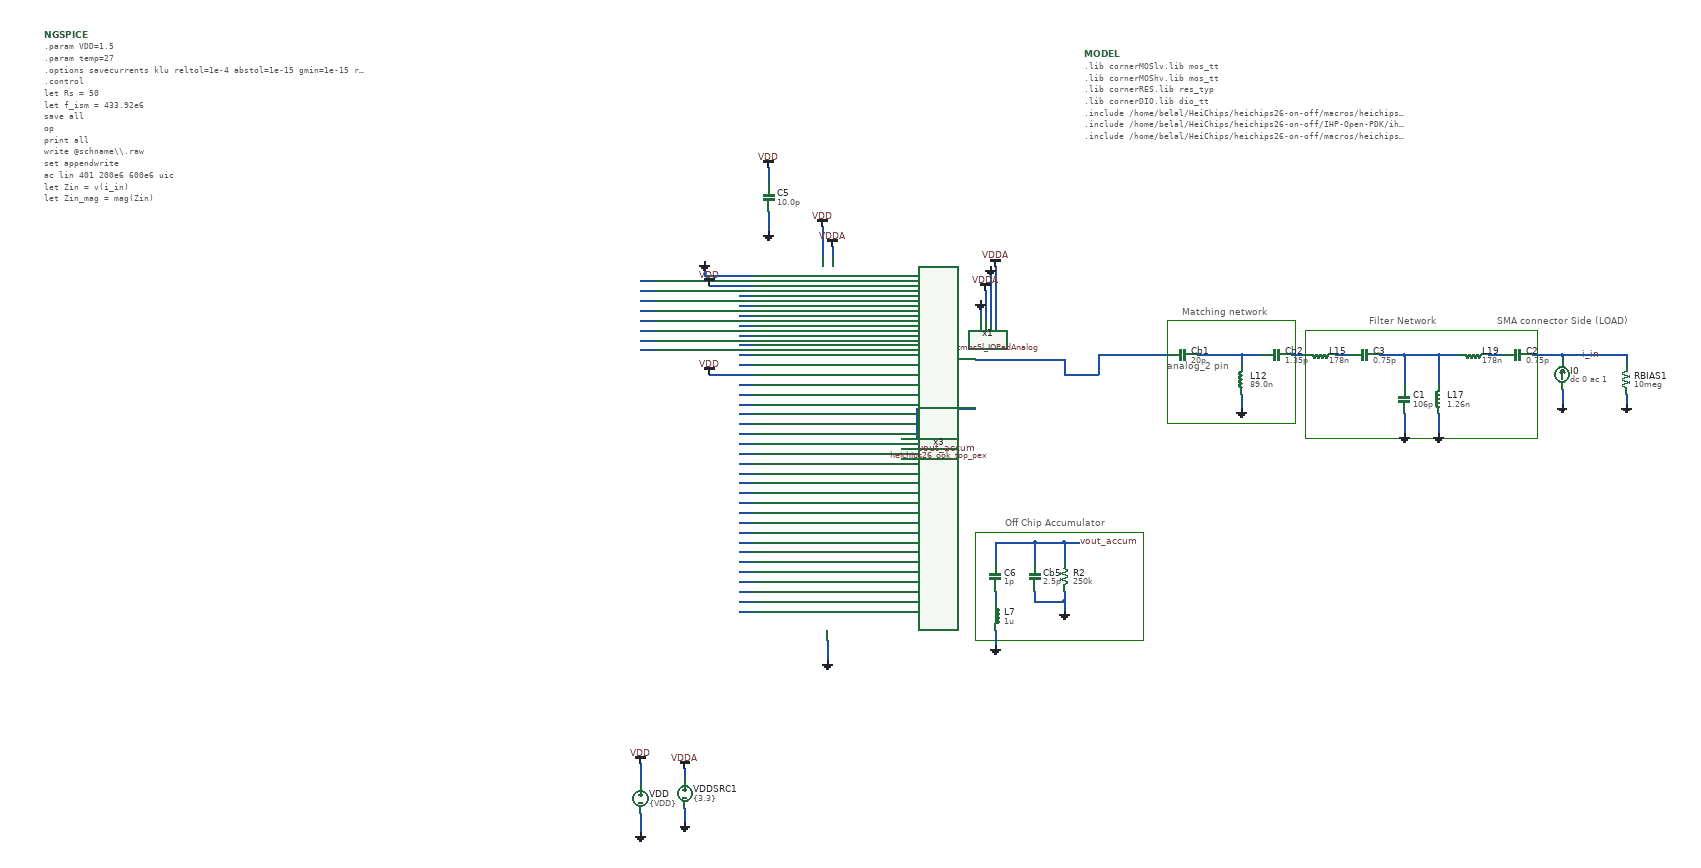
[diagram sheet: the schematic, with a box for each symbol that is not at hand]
v {xschem version=3.4.8RC file_version=1.3}
G {}
K {}
V {}
S {}
F {}
E {}
P 4 6 820 -740 820 -540 1160 -540 1160 -760 820 -760 820 -740 {}
P 4 7 1220 -1190 1470 -1190 1470 -980 1210 -980 1210 -1190 1230 -1190 1220 -1190 {}
P 4 5 1490 -1170 1960 -1170 1960 -950 1490 -950 1490 -1170 {}
T {Off Chip Accumulator} 880 -790 0 0 0.4 0.4 {}
T {Matching network} 1240 -1220 0 0 0.4 0.4 {}
T {Filter Network} 1620 -1200 0 0 0.4 0.4 {}
T {SMA connector Side (LOAD)} 1880 -1200 0 0 0.4 0.4 {}
T {analog_2 pin} 1210 -1110 1 0 0.4 0.4 {}
N 830 -1230 830 -1200 {lab=GND}
N 850 -1300 850 -1180 {lab=GND}
N 860 -1300 860 -1170 {lab=VDDA}
N 840 -1250 840 -1190 {lab=VDDA}
N 820 -1110 1000 -1110 {lab=#net1}
N 1000 -1110 1000 -1080 {lab=#net1}
N 510 -1380 510 -1320 {lab=VDD}
N 530 -1340 530 -1320 {lab=VDDA}
N 280 -1260 370 -1260 {lab=VDD}
N 340 -660 370 -660 {lab=#net2}
N 340 -640 370 -640 {lab=#net3}
N 340 -620 370 -620 {lab=#net4}
N 340 -600 370 -600 {lab=#net5}
N 670 -930 700 -930 {lab=vout_accum}
N 340 -1240 370 -1240 {lab=#net6}
N 340 -1220 370 -1220 {lab=#net7}
N 340 -1200 370 -1200 {lab=#net8}
N 340 -1180 370 -1180 {lab=#net9}
N 340 -1160 370 -1160 {lab=#net10}
N 340 -1140 370 -1140 {lab=#net11}
N 340 -1120 370 -1120 {lab=#net12}
N 340 -1100 370 -1100 {lab=#net13}
N 340 -1060 370 -1060 {lab=#net14}
N 340 -1040 370 -1040 {lab=#net15}
N 340 -1020 370 -1020 {lab=#net16}
N 340 -1000 370 -1000 {lab=#net17}
N 340 -980 370 -980 {lab=#net18}
N 340 -960 370 -960 {lab=#net19}
N 340 -940 370 -940 {lab=#net20}
N 340 -920 370 -920 {lab=#net21}
N 340 -900 370 -900 {lab=#net22}
N 340 -880 370 -880 {lab=#net23}
N 340 -860 370 -860 {lab=#net24}
N 340 -840 370 -840 {lab=#net25}
N 340 -820 370 -820 {lab=#net26}
N 340 -800 370 -800 {lab=#net27}
N 340 -780 370 -780 {lab=#net28}
N 340 -760 370 -760 {lab=#net29}
N 340 -740 370 -740 {lab=#net30}
N 340 -720 370 -720 {lab=#net31}
N 340 -700 370 -700 {lab=#net32}
N 340 -680 370 -680 {lab=#net33}
N 280 -1080 370 -1080 {lab=VDD}
N 140 -1270 170 -1270 {lab=#net34}
N 140 -1250 170 -1250 {lab=#net35}
N 140 -1230 170 -1230 {lab=#net36}
N 140 -1210 170 -1210 {lab=#net37}
N 140 -1190 170 -1190 {lab=#net38}
N 140 -1170 170 -1170 {lab=#net39}
N 140 -1150 170 -1150 {lab=#net40}
N 140 -1130 170 -1130 {lab=#net41}
N 520 -540 520 -500 {lab=GND}
N 270 -1310 270 -1280 {lab=GND}
N 270 -1280 370 -1280 {lab=GND}
N 400 -1500 400 -1470 {lab=VDD}
N 400 -1410 400 -1370 {lab=GND}
N 670 -950 700 -950 {lab=#net42}
N 1000 -740 1000 -700 {lab=vout_accum}
N 940 -740 940 -700 {lab=vout_accum}
N 940 -740 1000 -740 {lab=vout_accum}
N 940 -640 940 -620 {lab=GND}
N 940 -620 1000 -620 {lab=GND}
N 1000 -640 1000 -620 {lab=GND}
N 1000 -620 1000 -600 {lab=GND}
N 860 -560 860 -530 {lab=GND}
N 860 -740 860 -700 {lab=vout_accum}
N 860 -640 860 -620 {lab=#net43}
N 1000 -740 1030 -740 {lab=vout_accum}
N 860 -740 940 -740 {lab=vout_accum}
N 670 -910 700 -910 {lab=#net44}
N 2010 -1050 2010 -1020 {lab=GND}
N 2010 -1120 2010 -1110 {lab=i_in}
N 2140 -1040 2140 -1020 {lab=GND}
N 2140 -1120 2140 -1100 {lab=i_in}
N 700 -1010 820 -1010 {lab=#net42}
N 700 -1010 700 -950 {lab=#net42}
N 140 -290 140 -250 {lab=VDD}
N 140 -190 140 -150 {lab=GND}
N 230 -280 230 -260 {lab=VDDA}
N 230 -200 230 -170 {lab=GND}
N 1360 -1120 1360 -1100 {lab=#net45}
N 1360 -1040 1360 -1010 {lab=GND}
N 1000 -1080 1070 -1080 {lab=#net1}
N 1270 -1120 1360 -1120 {lab=#net45}
N 1070 -1120 1210 -1120 {lab=#net1}
N 1070 -1120 1070 -1080 {lab=#net1}
N 1360 -1120 1400 -1120 {lab=#net45}
N 1550 -1120 1580 -1120 {lab=#net46}
N 1760 -1120 1760 -1060 {lab=#net47}
N 1690 -1120 1760 -1120 {lab=#net47}
N 1690 -1120 1690 -1060 {lab=#net47}
N 1640 -1120 1690 -1120 {lab=#net47}
N 1690 -1000 1690 -960 {lab=GND}
N 1760 -1000 1760 -960 {lab=GND}
N 1760 -1120 1800 -1120 {lab=#net47}
N 1860 -1120 1890 -1120 {lab=#net48}
N 2010 -1120 2140 -1120 {lab=i_in}
N 1460 -1120 1490 -1120 {lab=#net49}
N 1950 -1120 2010 -1120 {lab=i_in}
C {devices/code_shown.sym} -1070 -1770 0 0 {name=NGSPICE
only_toplevel=true
value="
.param VDD=1.5
.param temp=27
.options savecurrents klu reltol=1e-4 abstol=1e-15 gmin=1e-15 rshunt=1e9

.control
let Rs = 50
let f_ism = 433.92e6

save all
op
print all
write @schname\\\\\\\\.raw
set appendwrite

ac lin 401 200e6 600e6 uic

let Zin      = v(i_in)
let Zin_mag  = mag(Zin)
let Zin_re   = real(Zin)
let Zin_im   = imag(Zin)
let Zin_ph   = 180/PI*cphase(Zin)

let Zpin     = v(net1)
let Zpin_mag = mag(Zpin)
let Zpin_re  = real(Zpin)
let Zpin_im  = imag(Zpin)

let Gam    = (Zin - Rs)/(Zin + Rs)
let Gmag   = mag(Gam)
let S11_dB = db(Gmag)
let ML_dB  = -10*log10(1 - Gmag*Gmag)

remzerovec
write @schname\\\\\\.raw
unset appendwrite

meas ac Zmag_ism find Zin_mag  when frequency=$&f_ism
meas ac Zre_ism  find Zin_re   when frequency=$&f_ism
meas ac Zim_ism  find Zin_im   when frequency=$&f_ism
meas ac Zph_ism  find Zin_ph   when frequency=$&f_ism

meas ac Zpre_ism find Zpin_re  when frequency=$&f_ism
meas ac Zpim_ism find Zpin_im  when frequency=$&f_ism

meas ac S11_ism  find S11_dB   when frequency=$&f_ism
meas ac ML_ism   find ML_dB    when frequency=$&f_ism

echo
echo   Zin  magnitude = $&Zmag_ism ohm
echo   Zin  real      = $&Zre_ism ohm
echo   Zin  imag      = $&Zim_ism ohm
echo   Zin  phase     = $&Zph_ism deg
echo
echo   Zpin real      = $&Zpre_ism ohm
echo   Zpin imag      = $&Zpim_ism ohm
echo
echo   S11            = $&S11_ism dB
echo   mismatch loss  = $&ML_ism dB
echo

plot Zin_re Zin_im xlimit 200e6 600e6 ylabel 'Zin real / imag [ohm]' xlabel 'Frequency [Hz]'

.endc"}
C {title-3.sym} 0 0 0 0 {name=l2 author="Belal Elshinnawey" rev=1.0 lock=true}
C {devices/code_shown.sym} 1040 -1730 0 0 {name=MODEL only_toplevel=true
format="tcleval( @value )"
value="
.lib cornerMOSlv.lib mos_tt
.lib cornerMOShv.lib mos_tt
.lib cornerRES.lib res_typ
.lib cornerDIO.lib dio_tt
.include /home/belal/HeiChips/heichips26-on-off/macros/heichips26_ook_top/macros/ook_analog_system/netlist/pex/lna_magic_pex_3.spice
.include /home/belal/HeiChips/heichips26-on-off/IHP-Open-PDK/ihp-sg13cmos5l/libs.ref/sg13cmos5l_io/spice/sg13cmos5l_io.spi
.include /home/belal/HeiChips/heichips26-on-off/macros/heichips26_ook_top/netlist/pex/heichips26_ook_top_magic_pex_3.spice
"}
C {sg13cmos5l_IOPadAnalog.sym} 1170 -1210 3 1 {name=x1}
C {devices/gnd.sym} 830 -1230 2 0 {name=l13 lab=GND}
C {devices/gnd.sym} 850 -1300 2 0 {name=l18 lab=GND}
C {vdd.sym} 510 -1380 0 0 {name=lvddb2 lab=VDD}
C {vdd.sym} 530 -1340 0 0 {name=lvddb5 lab=VDDA
value=\{VDD/2\}}
C {noconn.sym} 340 -680 0 0 {name=l24}
C {noconn.sym} 340 -700 0 0 {name=l25}
C {noconn.sym} 340 -720 0 0 {name=l26}
C {noconn.sym} 340 -740 0 0 {name=l27}
C {noconn.sym} 340 -760 0 0 {name=l28}
C {noconn.sym} 340 -780 0 0 {name=l29}
C {noconn.sym} 340 -800 0 0 {name=l30}
C {noconn.sym} 340 -820 0 0 {name=l31}
C {noconn.sym} 340 -840 0 0 {name=l32}
C {noconn.sym} 340 -860 0 0 {name=l33}
C {noconn.sym} 340 -880 0 0 {name=l34}
C {noconn.sym} 340 -900 0 0 {name=l35}
C {noconn.sym} 340 -920 0 0 {name=l36}
C {noconn.sym} 340 -940 0 0 {name=l37}
C {noconn.sym} 340 -960 0 0 {name=l38}
C {noconn.sym} 340 -980 0 0 {name=l39}
C {noconn.sym} 340 -1000 0 0 {name=l40}
C {noconn.sym} 340 -1020 0 0 {name=l41}
C {noconn.sym} 340 -1040 0 0 {name=l42}
C {noconn.sym} 340 -1060 0 0 {name=l43}
C {noconn.sym} 340 -1100 0 0 {name=l44}
C {noconn.sym} 340 -1120 0 0 {name=l45}
C {noconn.sym} 340 -1140 0 0 {name=l46}
C {noconn.sym} 340 -1160 0 0 {name=l47}
C {noconn.sym} 340 -1180 0 0 {name=l48}
C {noconn.sym} 340 -1200 0 0 {name=l49}
C {noconn.sym} 340 -1220 0 0 {name=l50}
C {noconn.sym} 340 -1240 0 0 {name=l51}
C {noconn.sym} 140 -1130 0 0 {name=l52}
C {noconn.sym} 140 -1150 0 0 {name=l53}
C {noconn.sym} 140 -1170 0 0 {name=l54}
C {noconn.sym} 140 -1190 0 0 {name=l55}
C {noconn.sym} 140 -1210 0 0 {name=l56}
C {noconn.sym} 140 -1230 0 0 {name=l57}
C {noconn.sym} 140 -1250 0 0 {name=l58}
C {noconn.sym} 140 -1270 0 0 {name=l59}
C {devices/gnd.sym} 520 -500 0 0 {name=lgnd1 lab=GND}
C {heichips26_ook_top_pex.sym} 530 -930 0 0 {name=x3}
C {capa.sym} 400 -1440 0 0 {name=C5
m=1
value=10.0p
footprint=1206
device="ceramic capacitor"}
C {vdd.sym} 400 -1500 0 0 {name=lvddb7 lab=VDD}
C {devices/gnd.sym} 400 -1370 0 0 {name=lgnd2 lab=GND
value=\{VDD/2\}}
C {vdd.sym} 280 -1260 2 0 {name=l60 lab=VDD}
C {devices/gnd.sym} 270 -1310 2 0 {name=lgnd3 lab=GND
value=\{VDD/2\}}
C {vdd.sym} 280 -1080 3 0 {name=l62 lab=VDD}
C {noconn.sym} 700 -910 2 0 {name=l63}
C {noconn.sym} 340 -660 0 0 {name=l1}
C {noconn.sym} 340 -640 0 0 {name=l4}
C {noconn.sym} 340 -620 0 0 {name=l5}
C {noconn.sym} 340 -600 0 0 {name=l6}
C {capa.sym} 940 -670 0 1 {name=Cb5
m=1
value=2.5p
footprint=1206
device="ceramic capacitor"
}
C {res.sym} 1000 -670 2 1 {name=R2
value=250k
int=1206
device=resistor
m=1}
C {devices/gnd.sym} 1000 -600 0 1 {name=l3 lab=GND}
C {devices/lab_pin.sym} 1030 -740 2 0 {name=p7 sig_type=std_logic lab=vout_accum}
C {devices/gnd.sym} 860 -530 0 0 {name=lgnd8 lab=GND}
C {capa.sym} 860 -670 0 0 {name=C6
m=1
value=1p
footprint=1206
device="ceramic capacitor"}
C {ind.sym} 860 -590 0 0 {name=L7
m=1
value=1u
footprint=1206
device=inductor}
C {devices/lab_pin.sym} 700 -930 2 0 {name=p1 sig_type=std_logic lab=vout_accum}
C {devices/gnd.sym} 2010 -1020 0 1 {name=l8 lab=GND}
C {devices/lab_pin.sym} 2090 -1120 3 1 {name=l9 sig_type=std_logic lab=i_in}
C {isource.sym} 2010 -1080 2 1 {name=I0 value="dc 0 ac 1"}
C {capa.sym} 1240 -1120 1 1 {name=Cb1
m=1
value=20p
footprint=1206
device="ceramic capacitor"
}
C {res.sym} 2140 -1070 0 1 {name=RBIAS1 value=10meg footprint=1206 device=resistor m=1}
C {devices/gnd.sym} 2140 -1020 0 1 {name=l16 lab=GND}
C {vdd.sym} 860 -1300 0 0 {name=lvddb1 lab=VDDA
value=\{VDD/2\}}
C {vdd.sym} 840 -1250 0 0 {name=lvddb3 lab=VDDA
value=\{VDD/2\}}
C {devices/vsource.sym} 140 -220 0 0 {name=VDD value=\{VDD\}}
C {devices/gnd.sym} 140 -150 0 0 {name=l10 lab=GND}
C {vdd.sym} 140 -290 0 0 {name=l11 lab=VDD}
C {devices/vsource.sym} 230 -230 0 0 {name=VDDSRC1 value=\{3.3\}}
C {vdd.sym} 230 -280 0 0 {name=lvddb4 lab=VDDA
value=\{3.3\}}
C {devices/gnd.sym} 230 -170 0 0 {name=lgnd4 lab=GND
value=\{VDD/2\}}
C {capa.sym} 1430 -1120 1 1 {name=Cb2
m=1
value=1.35p
footprint=1206
device="ceramic capacitor"
}
C {ind.sym} 1360 -1070 0 1 {name=L12
m=1
value=89.0n
footprint=1206
device=inductor}
C {devices/gnd.sym} 1360 -1010 0 1 {name=l14 lab=GND}
C {capa.sym} 1610 -1120 3 1 {name=C3
m=1
value=0.75p
footprint=1206
device="ceramic capacitor"}
C {ind.sym} 1520 -1120 3 1 {name=L15
m=1
value=178n
footprint=1206
device=inductor}
C {capa.sym} 1690 -1030 0 1 {name=C1
m=1
value=106p
footprint=1206
device="ceramic capacitor"}
C {ind.sym} 1760 -1030 0 1 {name=L17
m=1
value=1.26n
footprint=1206
device=inductor}
C {devices/gnd.sym} 1690 -960 0 0 {name=lgndrload5 lab=GND}
C {devices/gnd.sym} 1760 -960 0 0 {name=lgndrload6 lab=GND}
C {capa.sym} 1920 -1120 3 1 {name=C2
m=1
value=0.75p
footprint=1206
device="ceramic capacitor"}
C {ind.sym} 1830 -1120 3 1 {name=L19
m=1
value=178n
footprint=1206
device=inductor}
